One B-rep face of a CAD part: STEP entity #6366.
In plain terms, the planar face has unit normal (0, 1, 0).
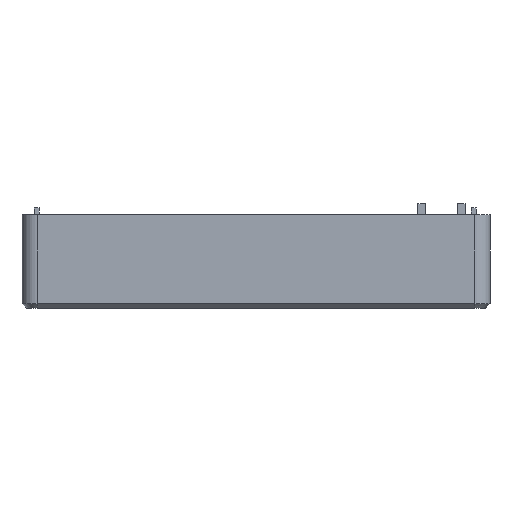
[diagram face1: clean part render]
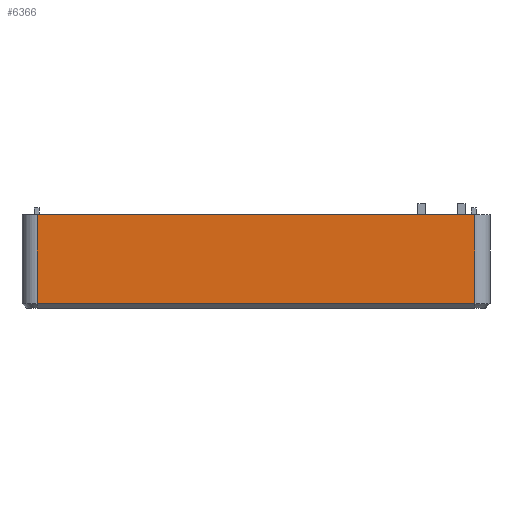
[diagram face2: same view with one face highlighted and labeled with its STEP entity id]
Its self-contained STEP definition (entity closure, numbers rounded to 3 decimals):
#765 = PLANE('',#766);
#766 = AXIS2_PLACEMENT_3D('',#767,#768,#769);
#767 = CARTESIAN_POINT('',(91.2,38.,22.1));
#768 = DIRECTION('',(0.,0.,1.));
#769 = DIRECTION('',(1.,0.,0.));
#2926 = VERTEX_POINT('',#2927);
#2927 = CARTESIAN_POINT('',(91.,73.,22.1));
#2942 = CYLINDRICAL_SURFACE('',#2943,3.2);
#2943 = AXIS2_PLACEMENT_3D('',#2944,#2945,#2946);
#2944 = CARTESIAN_POINT('',(91.,69.8,22.1));
#2945 = DIRECTION('',(-0.,-0.,-1.));
#2946 = DIRECTION('',(1.,0.,0.));
#2954 = EDGE_CURVE('',#2955,#2926,#2957,.T.);
#2955 = VERTEX_POINT('',#2956);
#2956 = CARTESIAN_POINT('',(-1.,73.,22.1));
#2957 = SURFACE_CURVE('',#2958,(#2962,#2969),.PCURVE_S1.);
#2958 = LINE('',#2959,#2960);
#2959 = CARTESIAN_POINT('',(45.,73.,22.1));
#2960 = VECTOR('',#2961,1.);
#2961 = DIRECTION('',(1.,0.,0.));
#2962 = PCURVE('',#765,#2963);
#2963 = DEFINITIONAL_REPRESENTATION('',(#2964),#2968);
#2964 = LINE('',#2965,#2966);
#2965 = CARTESIAN_POINT('',(-46.2,35.));
#2966 = VECTOR('',#2967,1.);
#2967 = DIRECTION('',(1.,0.));
#2968 = ( GEOMETRIC_REPRESENTATION_CONTEXT(2) 
PARAMETRIC_REPRESENTATION_CONTEXT() REPRESENTATION_CONTEXT('2D SPACE',''
  ) );
#2969 = PCURVE('',#2970,#2975);
#2970 = PLANE('',#2971);
#2971 = AXIS2_PLACEMENT_3D('',#2972,#2973,#2974);
#2972 = CARTESIAN_POINT('',(-1.,73.,22.1));
#2973 = DIRECTION('',(0.,1.,0.));
#2974 = DIRECTION('',(1.,0.,0.));
#2975 = DEFINITIONAL_REPRESENTATION('',(#2976),#2980);
#2976 = LINE('',#2977,#2978);
#2977 = CARTESIAN_POINT('',(46.,0.));
#2978 = VECTOR('',#2979,1.);
#2979 = DIRECTION('',(1.,0.));
#2980 = ( GEOMETRIC_REPRESENTATION_CONTEXT(2) 
PARAMETRIC_REPRESENTATION_CONTEXT() REPRESENTATION_CONTEXT('2D SPACE',''
  ) );
#2997 = CYLINDRICAL_SURFACE('',#2998,3.2);
#2998 = AXIS2_PLACEMENT_3D('',#2999,#3000,#3001);
#2999 = CARTESIAN_POINT('',(-1.,69.8,22.1));
#3000 = DIRECTION('',(-0.,-0.,-1.));
#3001 = DIRECTION('',(1.,0.,0.));
#6316 = EDGE_CURVE('',#2955,#6317,#6319,.T.);
#6317 = VERTEX_POINT('',#6318);
#6318 = CARTESIAN_POINT('',(-1.,73.,40.8));
#6319 = SURFACE_CURVE('',#6320,(#6324,#6331),.PCURVE_S1.);
#6320 = LINE('',#6321,#6322);
#6321 = CARTESIAN_POINT('',(-1.,73.,22.1));
#6322 = VECTOR('',#6323,1.);
#6323 = DIRECTION('',(0.,0.,1.));
#6324 = PCURVE('',#2997,#6325);
#6325 = DEFINITIONAL_REPRESENTATION('',(#6326),#6330);
#6326 = LINE('',#6327,#6328);
#6327 = CARTESIAN_POINT('',(-1.571,0.));
#6328 = VECTOR('',#6329,1.);
#6329 = DIRECTION('',(-0.,-1.));
#6330 = ( GEOMETRIC_REPRESENTATION_CONTEXT(2) 
PARAMETRIC_REPRESENTATION_CONTEXT() REPRESENTATION_CONTEXT('2D SPACE',''
  ) );
#6331 = PCURVE('',#2970,#6332);
#6332 = DEFINITIONAL_REPRESENTATION('',(#6333),#6337);
#6333 = LINE('',#6334,#6335);
#6334 = CARTESIAN_POINT('',(0.,0.));
#6335 = VECTOR('',#6336,1.);
#6336 = DIRECTION('',(0.,-1.));
#6337 = ( GEOMETRIC_REPRESENTATION_CONTEXT(2) 
PARAMETRIC_REPRESENTATION_CONTEXT() REPRESENTATION_CONTEXT('2D SPACE',''
  ) );
#6366 = ADVANCED_FACE('',(#6367),#2970,.T.);
#6367 = FACE_BOUND('',#6368,.T.);
#6368 = EDGE_LOOP('',(#6369,#6370,#6398,#6419));
#6369 = ORIENTED_EDGE('',*,*,#6316,.T.);
#6370 = ORIENTED_EDGE('',*,*,#6371,.T.);
#6371 = EDGE_CURVE('',#6317,#6372,#6374,.T.);
#6372 = VERTEX_POINT('',#6373);
#6373 = CARTESIAN_POINT('',(91.,73.,40.8));
#6374 = SURFACE_CURVE('',#6375,(#6379,#6386),.PCURVE_S1.);
#6375 = LINE('',#6376,#6377);
#6376 = CARTESIAN_POINT('',(45.,73.,40.8));
#6377 = VECTOR('',#6378,1.);
#6378 = DIRECTION('',(1.,0.,0.));
#6379 = PCURVE('',#2970,#6380);
#6380 = DEFINITIONAL_REPRESENTATION('',(#6381),#6385);
#6381 = LINE('',#6382,#6383);
#6382 = CARTESIAN_POINT('',(46.,-18.7));
#6383 = VECTOR('',#6384,1.);
#6384 = DIRECTION('',(1.,0.));
#6385 = ( GEOMETRIC_REPRESENTATION_CONTEXT(2) 
PARAMETRIC_REPRESENTATION_CONTEXT() REPRESENTATION_CONTEXT('2D SPACE',''
  ) );
#6386 = PCURVE('',#6387,#6392);
#6387 = PLANE('',#6388);
#6388 = AXIS2_PLACEMENT_3D('',#6389,#6390,#6391);
#6389 = CARTESIAN_POINT('',(45.,72.,41.8));
#6390 = DIRECTION('',(-0.,0.707,0.707));
#6391 = DIRECTION('',(-1.,0.,-0.));
#6392 = DEFINITIONAL_REPRESENTATION('',(#6393),#6397);
#6393 = LINE('',#6394,#6395);
#6394 = CARTESIAN_POINT('',(0.,-1.414));
#6395 = VECTOR('',#6396,1.);
#6396 = DIRECTION('',(-1.,0.));
#6397 = ( GEOMETRIC_REPRESENTATION_CONTEXT(2) 
PARAMETRIC_REPRESENTATION_CONTEXT() REPRESENTATION_CONTEXT('2D SPACE',''
  ) );
#6398 = ORIENTED_EDGE('',*,*,#6399,.F.);
#6399 = EDGE_CURVE('',#2926,#6372,#6400,.T.);
#6400 = SURFACE_CURVE('',#6401,(#6405,#6412),.PCURVE_S1.);
#6401 = LINE('',#6402,#6403);
#6402 = CARTESIAN_POINT('',(91.,73.,22.1));
#6403 = VECTOR('',#6404,1.);
#6404 = DIRECTION('',(0.,0.,1.));
#6405 = PCURVE('',#2970,#6406);
#6406 = DEFINITIONAL_REPRESENTATION('',(#6407),#6411);
#6407 = LINE('',#6408,#6409);
#6408 = CARTESIAN_POINT('',(92.,0.));
#6409 = VECTOR('',#6410,1.);
#6410 = DIRECTION('',(0.,-1.));
#6411 = ( GEOMETRIC_REPRESENTATION_CONTEXT(2) 
PARAMETRIC_REPRESENTATION_CONTEXT() REPRESENTATION_CONTEXT('2D SPACE',''
  ) );
#6412 = PCURVE('',#2942,#6413);
#6413 = DEFINITIONAL_REPRESENTATION('',(#6414),#6418);
#6414 = LINE('',#6415,#6416);
#6415 = CARTESIAN_POINT('',(-1.571,0.));
#6416 = VECTOR('',#6417,1.);
#6417 = DIRECTION('',(-0.,-1.));
#6418 = ( GEOMETRIC_REPRESENTATION_CONTEXT(2) 
PARAMETRIC_REPRESENTATION_CONTEXT() REPRESENTATION_CONTEXT('2D SPACE',''
  ) );
#6419 = ORIENTED_EDGE('',*,*,#2954,.F.);
